One B-rep face of a CAD part: STEP entity #225.
In plain terms, the planar face has unit normal (1, 0, 0).
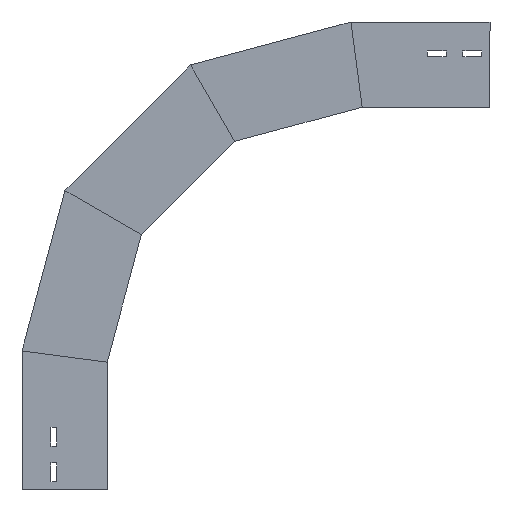
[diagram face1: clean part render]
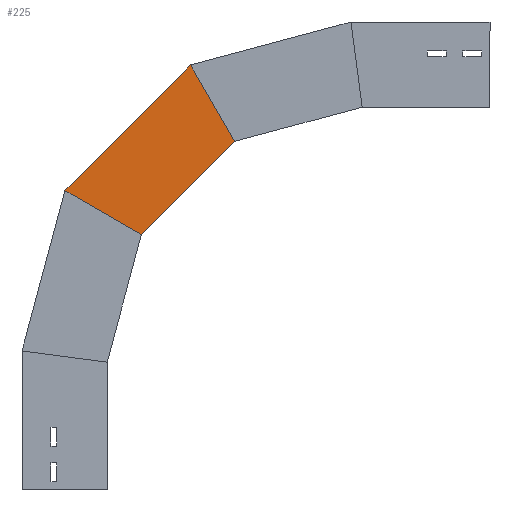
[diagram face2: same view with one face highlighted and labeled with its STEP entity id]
Its self-contained STEP definition (entity closure, numbers rounded to 3 decimals):
#57 = VERTEX_POINT ( 'NONE', #654 ) ;
#78 = VERTEX_POINT ( 'NONE', #511 ) ;
#101 = DIRECTION ( 'NONE',  ( 0., -0.707, 0.707 ) ) ;
#143 = VERTEX_POINT ( 'NONE', #389 ) ;
#225 = ADVANCED_FACE ( 'NONE', ( #456 ), #1745, .T. ) ;
#279 = CARTESIAN_POINT ( 'NONE',  ( 0., -19.205, 278.806 ) ) ;
#304 = ORIENTED_EDGE ( 'NONE', *, *, #894, .F. ) ;
#389 = CARTESIAN_POINT ( 'NONE',  ( 0., -149.719, 409.32 ) ) ;
#390 = ORIENTED_EDGE ( 'NONE', *, *, #707, .T. ) ;
#456 = FACE_OUTER_BOUND ( 'NONE', #836, .T. ) ;
#511 = CARTESIAN_POINT ( 'NONE',  ( 0., -97.955, 498.978 ) ) ;
#586 = DIRECTION ( 'NONE',  ( 0., 0., -1. ) ) ;
#654 = CARTESIAN_POINT ( 'NONE',  ( 0., -40.117, 299.719 ) ) ;
#677 = CARTESIAN_POINT ( 'NONE',  ( 0., -173.604, 367.949 ) ) ;
#700 = DIRECTION ( 'NONE',  ( 0., -0.5, -0.866 ) ) ;
#707 = EDGE_CURVE ( 'NONE', #78, #143, #1264, .T. ) ;
#753 = LINE ( 'NONE', #1029, #1015 ) ;
#806 = DIRECTION ( 'NONE',  ( 0., -0.707, 0.707 ) ) ;
#836 = EDGE_LOOP ( 'NONE', ( #1877, #390, #1678, #304 ) ) ;
#894 = EDGE_CURVE ( 'NONE', #1278, #57, #753, .T. ) ;
#963 = CARTESIAN_POINT ( 'NONE',  ( 0., 51.506, 349.517 ) ) ;
#989 = DIRECTION ( 'NONE',  ( 1., 0., 0. ) ) ;
#1015 = VECTOR ( 'NONE', #1463, 1000. ) ;
#1029 = CARTESIAN_POINT ( 'NONE',  ( 0., -78.128, 277.773 ) ) ;
#1072 = EDGE_CURVE ( 'NONE', #57, #143, #1077, .T. ) ;
#1076 = VECTOR ( 'NONE', #806, 1000. ) ;
#1077 = LINE ( 'NONE', #1674, #1076 ) ;
#1257 = AXIS2_PLACEMENT_3D ( 'NONE', #279, #989, #586 ) ;
#1264 = LINE ( 'NONE', #677, #1356 ) ;
#1278 = VERTEX_POINT ( 'NONE', #1451 ) ;
#1356 = VECTOR ( 'NONE', #700, 1000. ) ;
#1398 = EDGE_CURVE ( 'NONE', #1278, #78, #1698, .T. ) ;
#1451 = CARTESIAN_POINT ( 'NONE',  ( 0., 49.541, 351.482 ) ) ;
#1463 = DIRECTION ( 'NONE',  ( 0., -0.866, -0.5 ) ) ;
#1674 = CARTESIAN_POINT ( 'NONE',  ( 0., -19.205, 278.806 ) ) ;
#1678 = ORIENTED_EDGE ( 'NONE', *, *, #1072, .F. ) ;
#1698 = LINE ( 'NONE', #963, #1738 ) ;
#1738 = VECTOR ( 'NONE', #101, 1000. ) ;
#1745 = PLANE ( 'NONE',  #1257 ) ;
#1877 = ORIENTED_EDGE ( 'NONE', *, *, #1398, .T. ) ;
